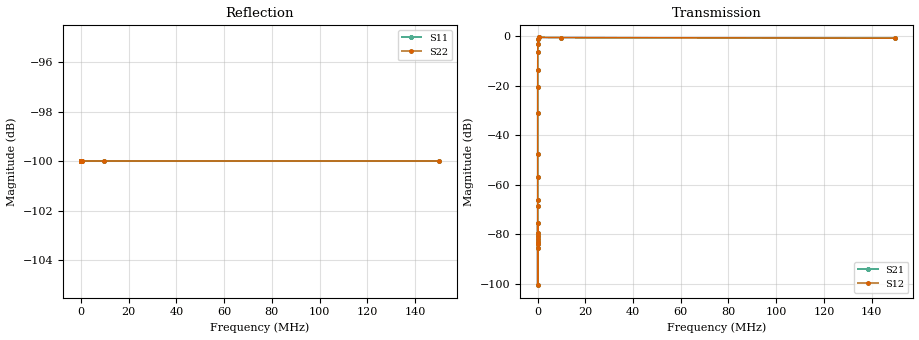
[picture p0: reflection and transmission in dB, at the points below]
! 8/13/2020 8:23 AM
! H:\MS4647B\Production_Data\9447\100\100_2020-08-12_16-29-16_LF_s2p.s2p
! CORRECTED DATA
# Hz S DB R 50.0
! FREQ  S11DB  S11A  S21DB  S21A  S12DB  S12A  S22DB  S22A
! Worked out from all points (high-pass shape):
!   401 points, 10 Hz to 150 MHz, reference 50 ohm
!   highest |S21| = -0.37 dB at 481.3 kHz (marker M1); lowest = -100.6 dB at 31.79 Hz (marker M2)
!   |S21| within 3 dB of the highest: 59.98 kHz to end of sweep
!   lowest |S11| = -100.0 dB at 10 Hz (marker M3), VSWR 1.00, Z = 50 + j0 ohm
!   |S11| at or under -10 dB: start of sweep to end of sweep
!   |S22| runs from -100.0 to -100.0 dB; largest |S21 - S12| = 0
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10  -100.00 0.0  -84.10 -84.1  -84.10 -84.1  -100.00 0.0
11.79671  -100.00 0.0  -83.23 -83.2  -83.23 -83.2  -100.00 0.0
12.81272  -100.00 0.0  -85.49 -85.5  -85.49 -85.5  -100.00 0.0
13.91624  -100.00 0.0  -75.39 -75.4  -75.39 -75.4  -100.00 0.0
15.75225  -100.00 0.0  -80.64 -80.6  -80.64 -80.6  -100.00 0.0
31.79263  -100.00 0.0  -100.64 -100.6  -100.64 -100.6  -100.00 0.0
129.5073  -100.00 0.0  -82.07 -82.1  -82.07 -82.1  -100.00 0.0
159.2191  -100.00 0.0  -79.63 -79.6  -79.63 -79.6  -100.00 0.0
485.7149  -100.00 0.0  -68.80 -68.8  -68.80 -68.8  -100.00 0.0
597.1488  -100.00 0.0  -66.35 -66.4  -66.35 -66.4  -100.00 0.0
1364.229  -100.00 0.0  -56.75 -56.7  -56.75 -56.7  -100.00 0.0
2535.074  -100.00 0.0  -47.66 -47.7  -47.66 -47.7  -100.00 0.0
7120.267  -100.00 0.0  -31.00 -31.0  -31.00 -31.0  -100.00 0.0
13789.23  -100.00 0.0  -20.28 -20.3  -20.28 -20.3  -100.00 0.0
21721.13  -100.00 0.0  -13.46 -13.5  -13.46 -13.5  -100.00 0.0
40363.22  -100.00 0.0  -6.30 -6.3  -6.30 -6.3  -100.00 0.0
66262.62  -100.00 0.0  -2.85 -2.8  -2.85 -2.8  -100.00 0.0
118149.5  -100.00 0.0  -1.08 -1.1  -1.08 -1.1  -100.00 0.0
481281.9  -100.00 0.0  -0.37 -0.4  -0.37 -0.4  -100.00 0.0
616653.1  -100.00 0.0  -0.37 -0.4  -0.37 -0.4  -100.00 0.0
9818298  -100.00 0.0  -0.46 -0.5  -0.46 -0.5  -100.00 0.0
1.5e8  -100.00 0.0  -0.68 -0.7  -0.68 -0.7  -100.00 0.0
